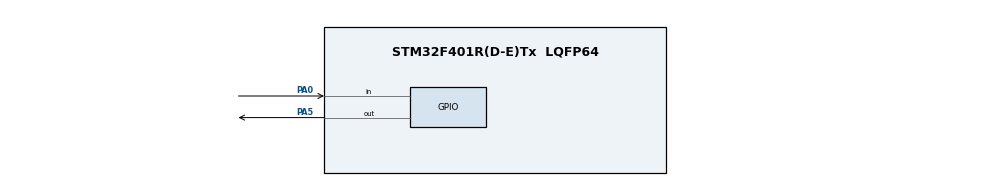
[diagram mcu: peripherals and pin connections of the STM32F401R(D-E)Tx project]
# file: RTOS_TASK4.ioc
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Mcu.Family=STM32F4
Mcu.Name=STM32F401R(D-E)Tx
Mcu.Package=LQFP64
NVIC.PriorityGroup=NVIC_PRIORITYGROUP_4
PA0-WKUP.GPIO_PuPd=GPIO_PULLDOWN
PA0-WKUP.Signal=GPIO_Input
PA13.Mode=Serial_Wire
PA13.Signal=SYS_JTMS-SWDIO
PA14.Mode=Serial_Wire
PA14.Signal=SYS_JTCK-SWCLK
PA5.Signal=GPIO_Output
PH0\ -\ OSC_IN.Mode=HSE-External-Oscillator
PH0\ -\ OSC_IN.Signal=RCC_OSC_IN
PH1\ -\ OSC_OUT.Mode=HSE-External-Oscillator
PH1\ -\ OSC_OUT.Signal=RCC_OSC_OUT
ProjectManager.HeapSize=0x200
ProjectManager.StackSize=0x400
ProjectManager.TargetToolchain=STM32CubeIDE
RCC.AHBFreq_Value=8000000
RCC.APB1Freq_Value=8000000
RCC.APB1TimFreq_Value=8000000
RCC.APB2Freq_Value=8000000
RCC.APB2TimFreq_Value=8000000
RCC.CortexFreq_Value=8000000
RCC.HCLKFreq_Value=8000000
RCC.HSE_VALUE=8000000
RCC.HSI_VALUE=16000000
RCC.LSE_VALUE=32768
RCC.SYSCLKFreq_VALUE=8000000
RCC.SYSCLKSource=RCC_SYSCLKSOURCE_HSE
RCC.VCOOutputFreq_Value=192000000
board=custom

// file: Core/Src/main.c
/* USER CODE BEGIN Header */
/**
  ******************************************************************************
  * @file           : main.c
  * @brief          : Main program body
  ******************************************************************************
  * @attention
  *
  * Copyright (c) 2022 STMicroelectronics.
  * All rights reserved.
  *
  * This software is licensed under terms that can be found in the LICENSE file
  * in the root directory of this software component.
  * If no LICENSE file comes with this software, it is provided AS-IS.
  *
  ******************************************************************************
  */
/* USER CODE END Header */
#include "main.h"
#include "FreeRTOS.h"
#include "task.h"

void SystemClock_Config(void);
static void MX_GPIO_Init(void);

/* Define Tasks Priorities */
#define  Motor_code_PRIORITY (2)
#define  ButtonOn_PRIORITY (2)

void Motor_code(void*pvParamter) ;
void ButtonIntro_code (void * pvParamter) ;
/*Create Task Handles Create */
xTaskHandle Task1Hand = NULL;
xTaskHandle Task2Hand = NULL;
char flag = 0 ;

int main(void)
{

  /* MCU Configuration--------------------------------------------------------*/

  /* Reset of all peripherals, Initializes the Flash interface and the Systick. */
  HAL_Init();

  /* Configure the system clock */
  SystemClock_Config();

  /* Initialize all configured peripherals */
  MX_GPIO_Init();

  /* Infinite loop */
  /* USER CODE BEGIN WHILE */

	xTaskCreate(Motor_code,"Task1",85,NULL,Motor_code_PRIORITY,&Task1Hand);

	xTaskCreate(ButtonIntro_code,"Task2",85,NULL,ButtonOn_PRIORITY,&Task2Hand);

	/*start Scheduler */
	vTaskStartScheduler();
  while (1)
  {
    /* USER CODE END WHILE */

  }
}

void SystemClock_Config(void)
{
  RCC_OscInitTypeDef RCC_OscInitStruct = {0};
  RCC_ClkInitTypeDef RCC_ClkInitStruct = {0};

  /** Configure the main internal regulator output voltage
  */
  __HAL_RCC_PWR_CLK_ENABLE();
  __HAL_PWR_VOLTAGESCALING_CONFIG(PWR_REGULATOR_VOLTAGE_SCALE2);

  /** Initializes the RCC Oscillators according to the specified parameters
  * in the RCC_OscInitTypeDef structure.
  */
  RCC_OscInitStruct.OscillatorType = RCC_OSCILLATORTYPE_HSI;
  RCC_OscInitStruct.HSIState = RCC_HSI_ON;
  RCC_OscInitStruct.HSICalibrationValue = RCC_HSICALIBRATION_DEFAULT;
  RCC_OscInitStruct.PLL.PLLState = RCC_PLL_NONE;
  if (HAL_RCC_OscConfig(&RCC_OscInitStruct) != HAL_OK)
  {
    Error_Handler();
  }

  /** Initializes the CPU, AHB and APB buses clocks
  */
  RCC_ClkInitStruct.ClockType = RCC_CLOCKTYPE_HCLK|RCC_CLOCKTYPE_SYSCLK
                              |RCC_CLOCKTYPE_PCLK1|RCC_CLOCKTYPE_PCLK2;
  RCC_ClkInitStruct.SYSCLKSource = RCC_SYSCLKSOURCE_HSI;
  RCC_ClkInitStruct.AHBCLKDivider = RCC_SYSCLK_DIV1;
  RCC_ClkInitStruct.APB1CLKDivider = RCC_HCLK_DIV1;
  RCC_ClkInitStruct.APB2CLKDivider = RCC_HCLK_DIV1;

  if (HAL_RCC_ClockConfig(&RCC_ClkInitStruct, FLASH_LATENCY_0) != HAL_OK)
  {
    Error_Handler();
  }
}

static void MX_GPIO_Init(void)
{
  GPIO_InitTypeDef GPIO_InitStruct = {0};

  /* GPIO Ports Clock Enable */
  __HAL_RCC_GPIOH_CLK_ENABLE();
  __HAL_RCC_GPIOA_CLK_ENABLE();
  __HAL_RCC_GPIOC_CLK_ENABLE();
  /*Configure GPIO pin Output Level */
  HAL_GPIO_WritePin(GPIOA, GPIO_PIN_5, GPIO_PIN_RESET);

  /*Configure GPIO pin : PA0 */
  GPIO_InitStruct.Pin = GPIO_PIN_13;
  GPIO_InitStruct.Mode = GPIO_MODE_INPUT;
  GPIO_InitStruct.Pull = GPIO_PULLDOWN;
  HAL_GPIO_Init(GPIOC, &GPIO_InitStruct);

  /*Configure GPIO pin : PA5 */
  GPIO_InitStruct.Pin = GPIO_PIN_5;
  GPIO_InitStruct.Mode = GPIO_MODE_OUTPUT_PP;
  GPIO_InitStruct.Pull = GPIO_NOPULL;
  GPIO_InitStruct.Speed = GPIO_SPEED_FREQ_LOW;
  HAL_GPIO_Init(GPIOA, &GPIO_InitStruct);

}

void Error_Handler(void)
{
  __disable_irq();
  while (1)
  {
  }
}

/*Task1 Code */
void Motor_code(void*pvParamter)
{

	while(1){

		vTaskDelay(100);
		if (flag == 1)
		{
			flag = 0;
			HAL_GPIO_TogglePin(GPIOA, GPIO_PIN_5);
			/*Send Task in Blocked Queue for 200 Ticks */
		}

	}

}

void ButtonIntro_code (void * pvParamter)
{

	while(1)
	{
		vTaskDelay(50);
		if (  HAL_GPIO_ReadPin(GPIOC, GPIO_PIN_13) == 0 )
		{
			while( HAL_GPIO_ReadPin(GPIOC, GPIO_PIN_13) == 0);
			vTaskDelay(3000);
			flag = 1 ;

		}

	}
}
